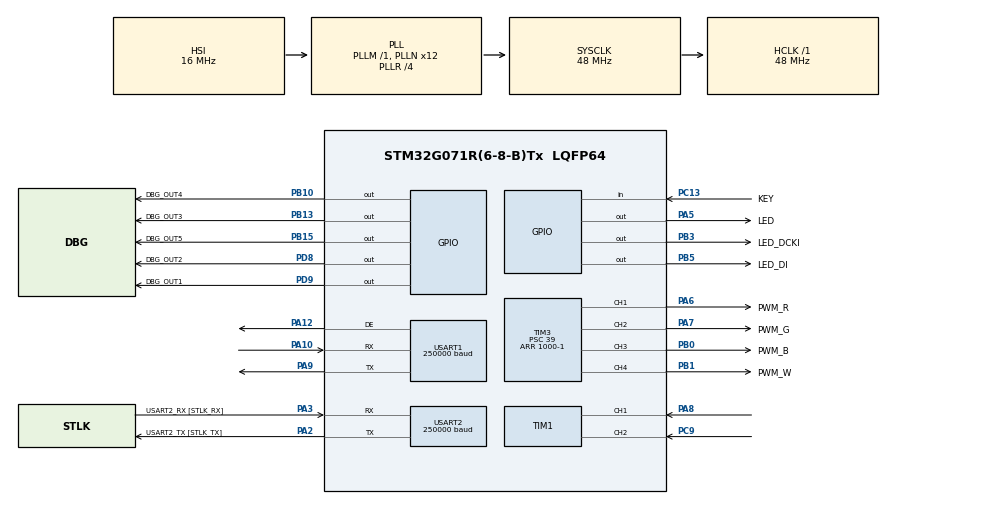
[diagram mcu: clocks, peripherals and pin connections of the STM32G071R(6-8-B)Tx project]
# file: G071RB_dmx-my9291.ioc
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Mcu.Family=STM32G0
Mcu.Name=STM32G071R(6-8-B)Tx
Mcu.Package=LQFP64
NVIC.TIM1_CC_IRQn=true\:0\:0\:false\:false\:true\:true\:true\:true
NVIC.USART1_IRQn=true\:0\:0\:false\:false\:true\:true\:true\:true
PA10.Mode=Asynchronous
PA10.Signal=USART1_RX
PA12\ [PA10].Mode=Hardware Flow Control (RS485)
PA12\ [PA10].Signal=USART1_DE
PA13.GPIO_Label=TMS
PA13.Mode=Serial_Wire
PA13.Signal=SYS_SWDIO
PA14-BOOT0.GPIO_Label=TCK
PA14-BOOT0.Mode=Serial_Wire
PA14-BOOT0.Signal=SYS_SWCLK
PA2.GPIO_Label=USART2_TX [STLK_TX]
PA2.GPIO_PuPd=GPIO_PULLUP
PA2.Mode=Asynchronous
PA2.Signal=USART2_TX
PA3.GPIO_Label=USART2_RX [STLK_RX]
PA3.GPIO_PuPd=GPIO_PULLUP
PA3.Mode=Asynchronous
PA3.Signal=USART2_RX
PA5.GPIO_Label=LED
PA5.GPIO_Speed=GPIO_SPEED_FREQ_LOW
PA5.Signal=GPIO_Output
PA6.GPIO_Label=PWM_R
PA6.Signal=S_TIM3_CH1
PA7.GPIO_Label=PWM_G
PA7.Signal=S_TIM3_CH2
PA8.Signal=S_TIM1_CH1
PA9.Mode=Asynchronous
PA9.Signal=USART1_TX
PB0.GPIO_Label=PWM_B
PB0.Signal=S_TIM3_CH3
PB1.GPIO_Label=PWM_W
PB1.Signal=S_TIM3_CH4
PB10.GPIO_Label=DBG_OUT4
PB10.Signal=GPIO_Output
PB13.GPIO_Label=DBG_OUT3
PB13.Signal=GPIO_Output
PB15.GPIO_Label=DBG_OUT5
PB15.Signal=GPIO_Output
PB3.GPIO_Label=LED_DCKI
PB3.Signal=GPIO_Output
PB5.GPIO_Label=LED_DI
PB5.Signal=GPIO_Output
PC13.GPIO_Label=KEY
PC13.Signal=GPIO_Input
PC14-OSC32_IN\ (PC14).Signal=RCC_OSC32_IN
PC15-OSC32_OUT\ (PC15).Signal=RCC_OSC32_OUT
PC9.Signal=S_TIM1_CH2
PD8.GPIO_Label=DBG_OUT2
PD8.Signal=GPIO_Output
PD9.GPIO_Label=DBG_OUT1
PD9.Signal=GPIO_Output
PF0-OSC_IN\ (PF0).GPIO_Label=MCO
PF0-OSC_IN\ (PF0).Signal=RCC_OSC_IN
ProjectManager.HeapSize=0x200
ProjectManager.StackSize=0x400
ProjectManager.TargetToolchain=STM32CubeIDE
RCC.ADCFreq_Value=48000000
RCC.AHBFreq_Value=48000000
RCC.APB1CLKDivider=RCC_HCLK_DIV2
RCC.CortexFreq_Value=48000000
RCC.EXTERNAL_CLOCK_VALUE=12288000
RCC.HCLKFreq_Value=48000000
RCC.HSE_VALUE=8000000
RCC.HSI_VALUE=16000000
RCC.LSE_VALUE=32768
RCC.PLLN=12
RCC.PLLQ=RCC_PLLQ_DIV6
RCC.PLLR=RCC_PLLR_DIV4
RCC.SYSCLKFreq_VALUE=48000000
RCC.SYSCLKSource=RCC_SYSCLKSOURCE_PLLCLK
RCC.USART1CLockSelection=RCC_USART1CLKSOURCE_SYSCLK
RCC.USART2CLockSelection=RCC_USART2CLKSOURCE_SYSCLK
RCC.VCOOutputFreq_Value=192000000
SH.S_TIM1_CH1.0=TIM1_CH1,Input_Capture1_from_TI1
SH.S_TIM1_CH2.0=TIM1_CH2,Input_Capture2_from_TI2
SH.S_TIM3_CH1.0=TIM3_CH1,PWM Generation1 CH1
SH.S_TIM3_CH2.0=TIM3_CH2,PWM Generation2 CH2
SH.S_TIM3_CH3.0=TIM3_CH3,PWM Generation3 CH3
SH.S_TIM3_CH4.0=TIM3_CH4,PWM Generation4 CH4
TIM1.Channel-Input_Capture1_from_TI1=TIM_CHANNEL_1
TIM1.Channel-Input_Capture2_from_TI2=TIM_CHANNEL_2
TIM1.ICPolarity_CH1=TIM_INPUTCHANNELPOLARITY_FALLING
TIM3.Channel-PWM\ Generation1\ CH1=TIM_CHANNEL_1
TIM3.Channel-PWM\ Generation2\ CH2=TIM_CHANNEL_2
TIM3.Channel-PWM\ Generation3\ CH3=TIM_CHANNEL_3
TIM3.Channel-PWM\ Generation4\ CH4=TIM_CHANNEL_4
TIM3.OCPolarity_1=TIM_OCPOLARITY_LOW
TIM3.OCPolarity_2=TIM_OCPOLARITY_LOW
TIM3.OCPolarity_3=TIM_OCPOLARITY_LOW
TIM3.OCPolarity_4=TIM_OCPOLARITY_LOW
TIM3.Period=1000-1
TIM3.Prescaler=39
TIM3.Pulse-PWM\ Generation1\ CH1=0
TIM3.Pulse-PWM\ Generation2\ CH2=0
TIM3.Pulse-PWM\ Generation3\ CH3=240
TIM3.Pulse-PWM\ Generation4\ CH4=0
USART1.BaudRate=250000
USART1.StopBits=STOPBITS_2
USART1.VirtualMode-Asynchronous=VM_ASYNC
USART1.VirtualMode-Hardware\ Flow\ Control\ (RS485)=VM_ASYNC
USART2.BaudRate=250000
USART2.VirtualMode-Asynchronous=VM_ASYNC
VP_SYS_VS_DBSignals.Mode=DisableDeadBatterySignals
VP_TIM1_VS_ClockSourceINT.Mode=Internal
VP_TIM3_VS_ClockSourceINT.Mode=Internal
board=NUCLEO-G071RB

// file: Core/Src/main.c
/* USER CODE BEGIN Header */
/**
 ******************************************************************************
 * @file           : main.c
 * @brief          : Main program body
 ******************************************************************************
 * @attention
 *
 * Copyright (c) 2024 STMicroelectronics.
 * All rights reserved.
 *
 * This software is licensed under terms that can be found in the LICENSE file
 * in the root directory of this software component.
 * If no LICENSE file comes with this software, it is provided AS-IS.
 *
 ******************************************************************************
 */
/* USER CODE END Header */
#include "main.h"

/* USER CODE BEGIN Includes */
#include "core.h"
//#include "curve.h"
//#include "led.h"

//#include "usb_device.h"
/* USER CODE END Includes */

/* USER CODE BEGIN PD */
#define PROG_NAME       "G071RB DMX512 slave\r\n"
#define PROG_VERSION    "(02/06/24) beta 1.2\r\n"

/* USER CODE END PD */

TIM_HandleTypeDef htim1;
TIM_HandleTypeDef htim3;

UART_HandleTypeDef huart1;
UART_HandleTypeDef huart2;

void SystemClock_Config(void);
static void MX_GPIO_Init(void);
static void MX_USART2_UART_Init(void);
static void MX_TIM3_Init(void);
static void MX_USART1_UART_Init(void);
static void MX_TIM1_Init(void);
/* USER CODE BEGIN PFP */
#ifdef __GNUC__
/* With GCC/RAISONANCE, small printf (option LD Linker->Libraries->Small printf
 set to 'Yes') calls __io_putchar() */
#define PUTCHAR_PROTOTYPE int __io_putchar(int ch)
#else
#define PUTCHAR_PROTOTYPE int fputc(int ch, FILE *f)
#endif /* __GNUC__ */

/* USER CODE END PFP */

/* USER CODE BEGIN 0 */
PUTCHAR_PROTOTYPE {
    /* Place your implementation of fputc here */
    /* e.g. write a character to the USART1 and Loop until the end of transmission */
    HAL_UART_Transmit(&huart2, (uint8_t*) &ch, 1, 0xFFFF);

    return ch;
}

/* USER CODE END 0 */

int main(void)
{

  /* MCU Configuration--------------------------------------------------------*/

  /* Reset of all peripherals, Initializes the Flash interface and the Systick. */
  HAL_Init();

  /* Configure the system clock */
  SystemClock_Config();

  /* Initialize all configured peripherals */
  MX_GPIO_Init();
  MX_USART2_UART_Init();
  MX_TIM3_Init();
  MX_USART1_UART_Init();
  MX_TIM1_Init();
  /* USER CODE BEGIN 2 */

    if (!core_init())
        Error_Handler();

    printf(PROG_NAME);
    printf(PROG_VERSION);

  /* USER CODE END 2 */

  /* Infinite loop */
  /* USER CODE BEGIN WHILE */
    DBG_OUT1();
    DBG_OUT2();
    DBG_OUT3();
    DBG_OUT4();
    DBG_OUT5();
    DBG_OUT6();
    DBG_OUT7();

    while (1) {

        core_process_h24();
        //RGBW_red();

    /* USER CODE END WHILE */

    }
}

void SystemClock_Config(void)
{
  RCC_OscInitTypeDef RCC_OscInitStruct = {0};
  RCC_ClkInitTypeDef RCC_ClkInitStruct = {0};

  /** Configure the main internal regulator output voltage
  */
  HAL_PWREx_ControlVoltageScaling(PWR_REGULATOR_VOLTAGE_SCALE1);

  /** Initializes the RCC Oscillators according to the specified parameters
  * in the RCC_OscInitTypeDef structure.
  */
  RCC_OscInitStruct.OscillatorType = RCC_OSCILLATORTYPE_HSI;
  RCC_OscInitStruct.HSIState = RCC_HSI_ON;
  RCC_OscInitStruct.HSIDiv = RCC_HSI_DIV1;
  RCC_OscInitStruct.HSICalibrationValue = RCC_HSICALIBRATION_DEFAULT;
  RCC_OscInitStruct.PLL.PLLState = RCC_PLL_ON;
  RCC_OscInitStruct.PLL.PLLSource = RCC_PLLSOURCE_HSI;
  RCC_OscInitStruct.PLL.PLLM = RCC_PLLM_DIV1;
  RCC_OscInitStruct.PLL.PLLN = 12;
  RCC_OscInitStruct.PLL.PLLP = RCC_PLLP_DIV2;
  RCC_OscInitStruct.PLL.PLLQ = RCC_PLLQ_DIV6;
  RCC_OscInitStruct.PLL.PLLR = RCC_PLLR_DIV4;
  if (HAL_RCC_OscConfig(&RCC_OscInitStruct) != HAL_OK)
  {
    Error_Handler();
  }

  /** Initializes the CPU, AHB and APB buses clocks
  */
  RCC_ClkInitStruct.ClockType = RCC_CLOCKTYPE_HCLK|RCC_CLOCKTYPE_SYSCLK
                              |RCC_CLOCKTYPE_PCLK1;
  RCC_ClkInitStruct.SYSCLKSource = RCC_SYSCLKSOURCE_PLLCLK;
  RCC_ClkInitStruct.AHBCLKDivider = RCC_SYSCLK_DIV1;
  RCC_ClkInitStruct.APB1CLKDivider = RCC_HCLK_DIV2;

  if (HAL_RCC_ClockConfig(&RCC_ClkInitStruct, FLASH_LATENCY_1) != HAL_OK)
  {
    Error_Handler();
  }
}

static void MX_TIM1_Init(void)
{

  TIM_ClockConfigTypeDef sClockSourceConfig = {0};
  TIM_MasterConfigTypeDef sMasterConfig = {0};
  TIM_IC_InitTypeDef sConfigIC = {0};

  htim1.Instance = TIM1;
  htim1.Init.Prescaler = 0;
  htim1.Init.CounterMode = TIM_COUNTERMODE_UP;
  htim1.Init.Period = 65535;
  htim1.Init.ClockDivision = TIM_CLOCKDIVISION_DIV1;
  htim1.Init.RepetitionCounter = 0;
  htim1.Init.AutoReloadPreload = TIM_AUTORELOAD_PRELOAD_DISABLE;
  if (HAL_TIM_Base_Init(&htim1) != HAL_OK)
  {
    Error_Handler();
  }
  sClockSourceConfig.ClockSource = TIM_CLOCKSOURCE_INTERNAL;
  if (HAL_TIM_ConfigClockSource(&htim1, &sClockSourceConfig) != HAL_OK)
  {
    Error_Handler();
  }
  if (HAL_TIM_IC_Init(&htim1) != HAL_OK)
  {
    Error_Handler();
  }
  sMasterConfig.MasterOutputTrigger = TIM_TRGO_RESET;
  sMasterConfig.MasterOutputTrigger2 = TIM_TRGO2_RESET;
  sMasterConfig.MasterSlaveMode = TIM_MASTERSLAVEMODE_DISABLE;
  if (HAL_TIMEx_MasterConfigSynchronization(&htim1, &sMasterConfig) != HAL_OK)
  {
    Error_Handler();
  }
  sConfigIC.ICPolarity = TIM_INPUTCHANNELPOLARITY_FALLING;
  sConfigIC.ICSelection = TIM_ICSELECTION_DIRECTTI;
  sConfigIC.ICPrescaler = TIM_ICPSC_DIV1;
  sConfigIC.ICFilter = 0;
  if (HAL_TIM_IC_ConfigChannel(&htim1, &sConfigIC, TIM_CHANNEL_1) != HAL_OK)
  {
    Error_Handler();
  }
  sConfigIC.ICPolarity = TIM_INPUTCHANNELPOLARITY_RISING;
  if (HAL_TIM_IC_ConfigChannel(&htim1, &sConfigIC, TIM_CHANNEL_2) != HAL_OK)
  {
    Error_Handler();
  }
  /* USER CODE BEGIN TIM1_Init 2 */

    __HAL_TIM_ENABLE_IT(&htim1, TIM_IT_UPDATE);

    TIM_CCxChannelCmd(htim1.Instance, TIM_CHANNEL_1, TIM_CCx_ENABLE);
    TIM_CCxChannelCmd(htim1.Instance, TIM_CHANNEL_2, TIM_CCx_ENABLE);

    __HAL_TIM_DISABLE_IT(&htim1, TIM_IT_CC1);
    __HAL_TIM_DISABLE_IT(&htim1, TIM_IT_CC2);

    __HAL_TIM_CLEAR_FLAG(&htim1, TIM_IT_CC1);
    __HAL_TIM_CLEAR_FLAG(&htim1, TIM_IT_CC2);

    __HAL_TIM_ENABLE(&htim1);

    /*-h24
     HAL_NVIC_SetPriority(TIM2_IRQn, 0, 0);
     HAL_NVIC_EnableIRQ(TIM2_IRQn);
     */
    HAL_NVIC_SetPriority(TIM1_CC_IRQn, 0, 0);
    HAL_NVIC_EnableIRQ(TIM1_CC_IRQn);

  /* USER CODE END TIM1_Init 2 */

}

static void MX_TIM3_Init(void)
{

  TIM_ClockConfigTypeDef sClockSourceConfig = {0};
  TIM_MasterConfigTypeDef sMasterConfig = {0};
  TIM_OC_InitTypeDef sConfigOC = {0};

  htim3.Instance = TIM3;
  htim3.Init.Prescaler = 39;
  htim3.Init.CounterMode = TIM_COUNTERMODE_UP;
  htim3.Init.Period = PWM_PERIOD-1;
  htim3.Init.ClockDivision = TIM_CLOCKDIVISION_DIV1;
  htim3.Init.AutoReloadPreload = TIM_AUTORELOAD_PRELOAD_DISABLE;
  if (HAL_TIM_Base_Init(&htim3) != HAL_OK)
  {
    Error_Handler();
  }
  sClockSourceConfig.ClockSource = TIM_CLOCKSOURCE_INTERNAL;
  if (HAL_TIM_ConfigClockSource(&htim3, &sClockSourceConfig) != HAL_OK)
  {
    Error_Handler();
  }
  if (HAL_TIM_PWM_Init(&htim3) != HAL_OK)
  {
    Error_Handler();
  }
  sMasterConfig.MasterOutputTrigger = TIM_TRGO_RESET;
  sMasterConfig.MasterSlaveMode = TIM_MASTERSLAVEMODE_DISABLE;
  if (HAL_TIMEx_MasterConfigSynchronization(&htim3, &sMasterConfig) != HAL_OK)
  {
    Error_Handler();
  }
  sConfigOC.OCMode = TIM_OCMODE_PWM1;
  sConfigOC.Pulse = 0;
  sConfigOC.OCPolarity = TIM_OCPOLARITY_LOW;
  sConfigOC.OCFastMode = TIM_OCFAST_DISABLE;
  if (HAL_TIM_PWM_ConfigChannel(&htim3, &sConfigOC, TIM_CHANNEL_1) != HAL_OK)
  {
    Error_Handler();
  }
  if (HAL_TIM_PWM_ConfigChannel(&htim3, &sConfigOC, TIM_CHANNEL_2) != HAL_OK)
  {
    Error_Handler();
  }
  sConfigOC.Pulse = PWM_B_INIT;
  if (HAL_TIM_PWM_ConfigChannel(&htim3, &sConfigOC, TIM_CHANNEL_3) != HAL_OK)
  {
    Error_Handler();
  }
  sConfigOC.Pulse = 0;
  if (HAL_TIM_PWM_ConfigChannel(&htim3, &sConfigOC, TIM_CHANNEL_4) != HAL_OK)
  {
    Error_Handler();
  }
  HAL_TIM_MspPostInit(&htim3);

}

static void MX_USART1_UART_Init(void)
{

  huart1.Instance = USART1;
  huart1.Init.BaudRate = 250000;
  huart1.Init.WordLength = UART_WORDLENGTH_8B;
  huart1.Init.StopBits = UART_STOPBITS_2;
  huart1.Init.Parity = UART_PARITY_NONE;
  huart1.Init.Mode = UART_MODE_TX_RX;
  huart1.Init.HwFlowCtl = UART_HWCONTROL_NONE;
  huart1.Init.OverSampling = UART_OVERSAMPLING_16;
  huart1.Init.OneBitSampling = UART_ONE_BIT_SAMPLE_DISABLE;
  huart1.Init.ClockPrescaler = UART_PRESCALER_DIV1;
  huart1.AdvancedInit.AdvFeatureInit = UART_ADVFEATURE_NO_INIT;
  if (HAL_RS485Ex_Init(&huart1, UART_DE_POLARITY_HIGH, 0, 0) != HAL_OK)
  {
    Error_Handler();
  }
  if (HAL_UARTEx_SetTxFifoThreshold(&huart1, UART_TXFIFO_THRESHOLD_1_8) != HAL_OK)
  {
    Error_Handler();
  }
  if (HAL_UARTEx_SetRxFifoThreshold(&huart1, UART_RXFIFO_THRESHOLD_1_8) != HAL_OK)
  {
    Error_Handler();
  }
  if (HAL_UARTEx_DisableFifoMode(&huart1) != HAL_OK)
  {
    Error_Handler();
  }
  /* USER CODE BEGIN USART1_Init 2 */
    __HAL_UART_ENABLE_IT(&huart1, UART_IT_RXNE);
    __HAL_UART_ENABLE_IT(&huart1, UART_IT_ERR);

  /* USER CODE END USART1_Init 2 */

}

static void MX_USART2_UART_Init(void)
{

  huart2.Instance = USART2;
  huart2.Init.BaudRate = 250000;
  huart2.Init.WordLength = UART_WORDLENGTH_8B;
  huart2.Init.StopBits = UART_STOPBITS_1;
  huart2.Init.Parity = UART_PARITY_NONE;
  huart2.Init.Mode = UART_MODE_TX_RX;
  huart2.Init.HwFlowCtl = UART_HWCONTROL_NONE;
  huart2.Init.OverSampling = UART_OVERSAMPLING_16;
  huart2.Init.OneBitSampling = UART_ONE_BIT_SAMPLE_DISABLE;
  huart2.Init.ClockPrescaler = UART_PRESCALER_DIV1;
  huart2.AdvancedInit.AdvFeatureInit = UART_ADVFEATURE_NO_INIT;
  if (HAL_UART_Init(&huart2) != HAL_OK)
  {
    Error_Handler();
  }
  if (HAL_UARTEx_SetTxFifoThreshold(&huart2, UART_TXFIFO_THRESHOLD_1_8) != HAL_OK)
  {
    Error_Handler();
  }
  if (HAL_UARTEx_SetRxFifoThreshold(&huart2, UART_RXFIFO_THRESHOLD_1_8) != HAL_OK)
  {
    Error_Handler();
  }
  if (HAL_UARTEx_DisableFifoMode(&huart2) != HAL_OK)
  {
    Error_Handler();
  }

}

static void MX_GPIO_Init(void)
{
  GPIO_InitTypeDef GPIO_InitStruct = {0};

  /* GPIO Ports Clock Enable */
  __HAL_RCC_GPIOC_CLK_ENABLE();
  __HAL_RCC_GPIOF_CLK_ENABLE();
  __HAL_RCC_GPIOA_CLK_ENABLE();
  __HAL_RCC_GPIOB_CLK_ENABLE();
  __HAL_RCC_GPIOD_CLK_ENABLE();

  /*Configure GPIO pin Output Level */
  HAL_GPIO_WritePin(LED_GPIO_Port, LED_Pin, GPIO_PIN_RESET);

  /*Configure GPIO pin Output Level */
  HAL_GPIO_WritePin(GPIOB, DBG_OUT7_Pin|DBG_OUT4_Pin|DBG_OUT3_Pin|DBG_OUT5_Pin
                          |LED_DCKI_Pin|LED_DI_Pin|DBG_OUT6_Pin, GPIO_PIN_RESET);

  /*Configure GPIO pin Output Level */
  HAL_GPIO_WritePin(GPIOD, DBG_OUT2_Pin|DBG_OUT1_Pin, GPIO_PIN_RESET);

  /*Configure GPIO pin : KEY_Pin */
  GPIO_InitStruct.Pin = KEY_Pin;
  GPIO_InitStruct.Mode = GPIO_MODE_INPUT;
  GPIO_InitStruct.Pull = GPIO_NOPULL;
  HAL_GPIO_Init(KEY_GPIO_Port, &GPIO_InitStruct);

  /*Configure GPIO pin : LED_Pin */
  GPIO_InitStruct.Pin = LED_Pin;
  GPIO_InitStruct.Mode = GPIO_MODE_OUTPUT_PP;
  GPIO_InitStruct.Pull = GPIO_NOPULL;
  GPIO_InitStruct.Speed = GPIO_SPEED_FREQ_LOW;
  HAL_GPIO_Init(LED_GPIO_Port, &GPIO_InitStruct);

  /*Configure GPIO pins : DBG_OUT7_Pin DBG_OUT4_Pin DBG_OUT3_Pin DBG_OUT5_Pin
                           LED_DCKI_Pin LED_DI_Pin DBG_OUT6_Pin */
  GPIO_InitStruct.Pin = DBG_OUT7_Pin|DBG_OUT4_Pin|DBG_OUT3_Pin|DBG_OUT5_Pin
                          |LED_DCKI_Pin|LED_DI_Pin|DBG_OUT6_Pin;
  GPIO_InitStruct.Mode = GPIO_MODE_OUTPUT_PP;
  GPIO_InitStruct.Pull = GPIO_NOPULL;
  GPIO_InitStruct.Speed = GPIO_SPEED_FREQ_LOW;
  HAL_GPIO_Init(GPIOB, &GPIO_InitStruct);

  /*Configure GPIO pins : DBG_OUT2_Pin DBG_OUT1_Pin */
  GPIO_InitStruct.Pin = DBG_OUT2_Pin|DBG_OUT1_Pin;
  GPIO_InitStruct.Mode = GPIO_MODE_OUTPUT_PP;
  GPIO_InitStruct.Pull = GPIO_NOPULL;
  GPIO_InitStruct.Speed = GPIO_SPEED_FREQ_LOW;
  HAL_GPIO_Init(GPIOD, &GPIO_InitStruct);

/* USER CODE BEGIN MX_GPIO_Init_2 */
    my92xx_init(MY92XX_MODEL, MY92XX_CHIPS, MY92XX_COMMAND_DEFAULT);
    my92xx_init_blue();

/* USER CODE END MX_GPIO_Init_2 */
}

void Error_Handler(void)
{
  /* USER CODE BEGIN Error_Handler_Debug */
    /* User can add his own implementation to report the HAL error return state */
    __disable_irq();
    while (1) {
        printf("error handler\r\n"); //+h24
    }
  /* USER CODE END Error_Handler_Debug */
}
